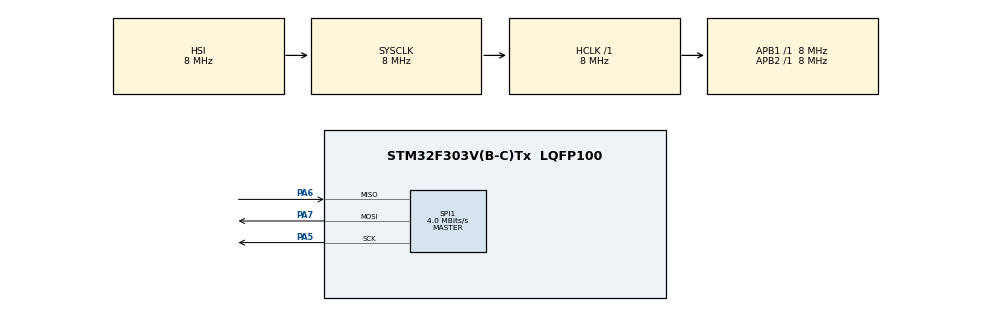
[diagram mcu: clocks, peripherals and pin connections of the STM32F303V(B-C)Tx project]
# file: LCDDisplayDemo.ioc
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Mcu.Family=STM32F3
Mcu.Name=STM32F303V(B-C)Tx
Mcu.Package=LQFP100
NVIC.PriorityGroup=NVIC_PRIORITYGROUP_4
PA5.Mode=Full_Duplex_Master
PA5.Signal=SPI1_SCK
PA6.Mode=Full_Duplex_Master
PA6.Signal=SPI1_MISO
PA7.Mode=Full_Duplex_Master
PA7.Signal=SPI1_MOSI
ProjectManager.HeapSize=0x200
ProjectManager.StackSize=0x400
ProjectManager.TargetToolchain=STM32CubeIDE
RCC.AHBFreq_Value=8000000
RCC.APB1Freq_Value=8000000
RCC.APB2Freq_Value=8000000
RCC.CortexFreq_Value=8000000
RCC.HSE_VALUE=8000000
RCC.HSI_VALUE=8000000
RCC.LSE_VALUE=32768
RCC.SYSCLKFreq_VALUE=8000000
SPI1.CalculateBaudRate=4.0 MBits/s
SPI1.Direction=SPI_DIRECTION_2LINES
SPI1.Mode=SPI_MODE_MASTER
SPI1.VirtualType=VM_MASTER
board=custom

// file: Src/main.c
/* USER CODE BEGIN Header */
/**
  ******************************************************************************
  * @file           : main.c
  * @brief          : Main program body
  ******************************************************************************
  * @attention
  *
  * <h2><center>&copy; Copyright (c) 2020 STMicroelectronics.
  * All rights reserved.</center></h2>
  *
  * This software component is licensed by ST under BSD 3-Clause license,
  * the "License"; You may not use this file except in compliance with the
  * License. You may obtain a copy of the License at:
  *                        opensource.org/licenses/BSD-3-Clause
  *
  ******************************************************************************
  */
/* USER CODE END Header */

#include "main.h"
#include "stm32f3xx_hal.h"
#include "ILI9341_Driver.h"
#include "Touch.h"
#include "display.h"

SPI_HandleTypeDef hspi1;
uint8_t state = 0;

void SystemClock_Config(void);
static void MX_GPIO_Init(void);
static void MX_SPI1_Init(void);

int main(void)
{

  /* MCU Configuration--------------------------------------------------------*/

  /* Reset of all peripherals, Initializes the Flash interface and the Systick. */
  HAL_Init();

  /* Configure the system clock */
  SystemClock_Config();

  /* Initialize all configured peripherals */
  MX_GPIO_Init();
  MX_SPI1_Init();

  /* =============Initialization=============== */
  ILI9341_Init();
//  ILI9341_Set_Rotation(0);
//  HAL_Delay(500);
//  ILI9341_Fill_Screen(BLUE);
//  ILI9341_Set_Rotation(1);
//  HAL_Delay(500);
//  ILI9341_Fill_Screen(GREEN);
//  ILI9341_Set_Rotation(2);
//  HAL_Delay(500);
//  ILI9341_Fill_Screen(BLUE);
//  HAL_Delay(500);

    /* ===============Draw menu================= */
    Display_Menu();

    uint16_t xtemp, ytemp;

//    while (1)
//      {
//  	  HAL_Delay(500);
//      }
	  TP_Init();
	  /* Infinite loop */
	  while (1)
	  {

		  tp_dev.scan(0);
		  if(tp_dev.sta & TP_PRES_DOWN)
		  {
			  xtemp = TP_Read_XOY(0xD0);
			  ytemp = TP_Read_XOY(0x90);

			  if(0 == state)
			  {
				  if(xtemp > 2700 && xtemp < 3400 && ytemp > 3000 && ytemp < 3500) {
					  Display_Color_Picture();
					  state = 1;
				  }

				  if(xtemp > 1200 && xtemp < 1900 && ytemp > 3000 && ytemp < 3500) {
					  Display_Text();
					  state = 1;
				  }
			  }
			  else
			  {
				  if(xtemp > 3400 && xtemp < 3900 && ytemp > 350 && ytemp < 750) {
					  Display_Menu();
					  state = 0;
				  }
			  }

			  HAL_Delay(500);
		  }

	  }
}

void SystemClock_Config(void)
{
  RCC_OscInitTypeDef RCC_OscInitStruct = {0};
  RCC_ClkInitTypeDef RCC_ClkInitStruct = {0};

  /** Initializes the CPU, AHB and APB busses clocks
  */
  RCC_OscInitStruct.OscillatorType = RCC_OSCILLATORTYPE_HSI;
  RCC_OscInitStruct.HSIState = RCC_HSI_ON;
  RCC_OscInitStruct.HSICalibrationValue = RCC_HSICALIBRATION_DEFAULT;
  RCC_OscInitStruct.PLL.PLLState = RCC_PLL_NONE;
  if (HAL_RCC_OscConfig(&RCC_OscInitStruct) != HAL_OK)
  {
    Error_Handler();
  }
  /** Initializes the CPU, AHB and APB busses clocks
  */
  RCC_ClkInitStruct.ClockType = RCC_CLOCKTYPE_HCLK|RCC_CLOCKTYPE_SYSCLK
                              |RCC_CLOCKTYPE_PCLK1|RCC_CLOCKTYPE_PCLK2;
  RCC_ClkInitStruct.SYSCLKSource = RCC_SYSCLKSOURCE_HSI;
  RCC_ClkInitStruct.AHBCLKDivider = RCC_SYSCLK_DIV1;
  RCC_ClkInitStruct.APB1CLKDivider = RCC_HCLK_DIV1;
  RCC_ClkInitStruct.APB2CLKDivider = RCC_HCLK_DIV1;

  if (HAL_RCC_ClockConfig(&RCC_ClkInitStruct, FLASH_LATENCY_0) != HAL_OK)
  {
    Error_Handler();
  }
}

static void MX_SPI1_Init(void)
{

  /* SPI1 parameter configuration*/
  hspi1.Instance = SPI1;
  hspi1.Init.Mode = SPI_MODE_MASTER;
  hspi1.Init.Direction = SPI_DIRECTION_2LINES;
  hspi1.Init.DataSize = SPI_DATASIZE_4BIT;
  hspi1.Init.CLKPolarity = SPI_POLARITY_LOW;
  hspi1.Init.CLKPhase = SPI_PHASE_1EDGE;
  hspi1.Init.NSS = SPI_NSS_SOFT;
  hspi1.Init.BaudRatePrescaler = SPI_BAUDRATEPRESCALER_2;
  hspi1.Init.FirstBit = SPI_FIRSTBIT_MSB;
  hspi1.Init.TIMode = SPI_TIMODE_DISABLE;
  hspi1.Init.CRCCalculation = SPI_CRCCALCULATION_DISABLE;
  hspi1.Init.CRCPolynomial = 7;
  hspi1.Init.CRCLength = SPI_CRC_LENGTH_DATASIZE;
  hspi1.Init.NSSPMode = SPI_NSS_PULSE_ENABLE;
  if (HAL_SPI_Init(&hspi1) != HAL_OK)
  {
    Error_Handler();
  }

}

static void MX_GPIO_Init(void)
{

  /* GPIO Ports Clock Enable */
//  __HAL_RCC_GPIOA_CLK_ENABLE();

	GPIO_InitTypeDef GPIO_InitStruct;

	/* GPIO Ports Clock Enable */
	__HAL_RCC_GPIOA_CLK_ENABLE();
	__HAL_RCC_GPIOB_CLK_ENABLE();
	__HAL_RCC_GPIOC_CLK_ENABLE();
	__HAL_RCC_GPIOD_CLK_ENABLE();
	__HAL_RCC_GPIOE_CLK_ENABLE();

	GPIO_InitStruct.Pin 	= DC_Pin | CS_Pin | RESET_Pin;
	GPIO_InitStruct.Mode 	= GPIO_MODE_OUTPUT_PP;
	GPIO_InitStruct.Pull 	= GPIO_NOPULL;
	GPIO_InitStruct.Speed 	= GPIO_SPEED_FREQ_LOW;
	HAL_GPIO_Init(GPIOA, &GPIO_InitStruct);

}

void Error_Handler(void)
{
}

/************************ (C) COPYRIGHT STMicroelectronics *****END OF FILE****/
